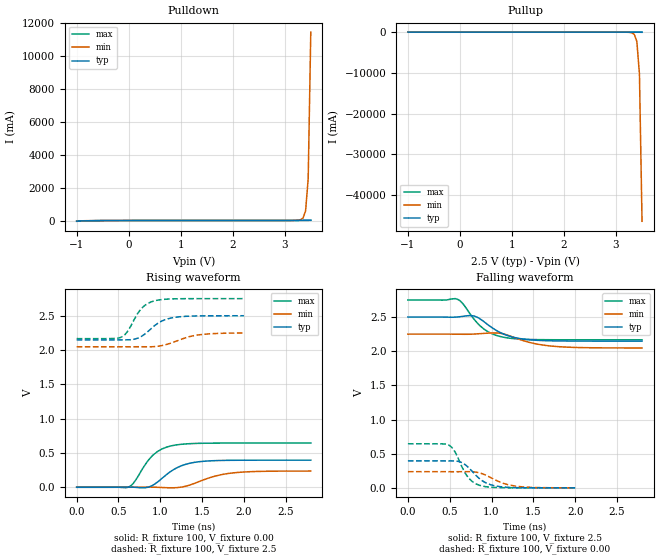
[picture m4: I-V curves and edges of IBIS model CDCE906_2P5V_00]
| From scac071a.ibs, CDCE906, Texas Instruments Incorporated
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|   Model   CDCE906_2P5V_00
[Model]   CDCE906_2P5V_00
Model_type   Output
Polarity   Non-Inverting
Vmeas  =   1.50V
Cref   =   3.00pF
Rref   =   100
Vref   =   0.00V
|Variable   typ   min   max
C_comp   1.472e-12   1.463e-12   1.490e-12
|Variable   typ   min   max
[Voltage range]   2.5   2.25   2.75
|Variable   typ   min   max
[Temperature range]  55   110   -15
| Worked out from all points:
|   slope of the pulldown table from 0 to 0.375 V, typ, clamps not added: 237 ohm
|   slope of the pullup table from 0 to 0.375 V, typ, clamps not added: 280 ohm
|   rising waveform, R_fixture 100, V_fixture 0.00: 20-80 % time 289ps typ, 368ps min, 242ps max; typ from 0 V to 0.395 V
|   falling waveform, R_fixture 100, V_fixture 2.5: 20-80 % time 309ps typ, 378ps min, 265ps max; typ from 2.5 V to 2.15 V
|   rising waveform, R_fixture 100, V_fixture 2.5: 20-80 % time 234ps typ, 304ps min, 184ps max; typ from 2.15 V to 2.5 V
|   falling waveform, R_fixture 100, V_fixture 0.00: 20-80 % time 216ps typ, 271ps min, 170ps max; typ from 0.395 V to 0 V
[Pulldown]
|Voltage   I(typ)   I(min)   I(max)
-1V       -35.71mA   -45.5mA    -45.21mA
-550mV    -3.792mA   -2.318mA   -6.183mA
3.15V     5.939mA    8.35mA     6.03mA
3.3V      9.436mA    45.5mA     7.442mA
3.35V     10.8mA     146.9mA    8.707mA
3.4V      12.31mA    585.3mA    10.16mA
3.45V     14.19mA    2.553A     11.78mA
3.5V      17.66mA    11.47A     13.54mA
[Pullup]
|Voltage   I(typ)   I(min)   I(max)
-1V       17.33mA    19.37mA    22.94mA
3.15V     -8.226mA   -15.73mA   -6.823mA
3.3V      -16.01mA   -135.6mA   -8.987mA
3.35V     -19.22mA   -527.9mA   -11.14mA
3.4V      -22.78mA   -2.287A    -13.98mA
3.45V     -27.22mA   -10.25A    -17.37mA
3.5V      -35.71mA   -46.44A    -21.23mA
[Ramp]
|Variable   typ   min   max
dV/dt_r  0.1198/2.217e-10   7.137e-02/3.024e-10   0.1977/1.698e-10
dV/dt_f  0.1063/2.346e-10   6.108e-02/3.162e-10   0.1762/1.879e-10
R_load  =  50
[Rising Waveform]
R_fixture   =   100
V_fixture   =   0.00
V_fixture_min   =   0.00
V_fixture_max   =   0.00
C_fixture   =   0.00
|Time   V(typ)   V(min)   V(max)
0s        0V         0V         0V
622.2ps   2.719mV    43.28uV    3.581mV
678.8ps   518.5uV    411.6uV    59.46mV
820.2ps   -6.651mV   2.31mV     330.3mV
905.1ps   25.58mV    1.538mV    459.4mV
1.018ns   127.5mV    -3.267mV   556.7mV
1.16ns    257.5mV    -7.72mV    610.2mV
1.414ns   363.9mV    59.48mV    638.4mV
1.838ns   392.7mV    204.7mV    644.1mV
2.8ns     394.9mV    236.3mV    644.6mV
[Falling Waveform]
R_fixture   =   100
V_fixture   =   2.5
V_fixture_min   =   2.25
V_fixture_max   =   2.75
C_fixture   =   0.00
|Time   V(typ)   V(min)   V(max)
0s        2.5V       2.25V      2.75V
593.9ps   2.501V     2.249V     2.76V
650.5ps   2.51V      2.248V     2.706V
791.9ps   2.515V     2.251V     2.466V
905.1ps   2.437V     2.261V     2.328V
1.018ns   2.334V     2.268V     2.249V
1.16ns    2.244V     2.248V     2.201V
1.358ns   2.182V     2.163V     2.177V
1.697ns   2.153V     2.078V     2.168V
2.8ns     2.148V     2.047V     2.167V
[Rising Waveform]
R_fixture   =   100
V_fixture   =   2.5
V_fixture_min   =   2.25
V_fixture_max   =   2.75
C_fixture   =   0.00
|Time   V(typ)   V(min)   V(max)
0s        2.147V     2.047V     2.166V
525.3ps   2.148V     2.047V     2.183V
606.1ps   2.149V     2.047V     2.266V
767.7ps   2.194V     2.048V     2.596V
848.5ps   2.266V     2.047V     2.677V
929.3ps   2.353V     2.05V      2.716V
1.051ns   2.439V     2.073V     2.739V
1.212ns   2.482V     2.139V     2.747V
1.495ns   2.498V     2.226V     2.749V
2ns       2.5V       2.249V     2.75V
[Falling Waveform]
R_fixture   =   100
V_fixture   =   0.00
V_fixture_min   =   0.00
V_fixture_max   =   0.00
C_fixture   =   0.00
|Time   V(typ)   V(min)   V(max)
0s        395.3mV    236.7mV    645.2mV
484.8ps   394.7mV    236.4mV    629.7mV
565.7ps   393.3mV    236.1mV    522.1mV
666.7ps   354.7mV    236.7mV    257.9mV
727.3ps   293.7mV    237mV      142mV
808.1ps   189.6mV    230.7mV    61.89mV
888.9ps   104.5mV    206.5mV    26.59mV
1.03ns    32.52mV    125.3mV    6.472mV
1.273ns   4.352mV    28.41mV    975.4uV
2ns       284.6uV    432.2uV    409.4uV
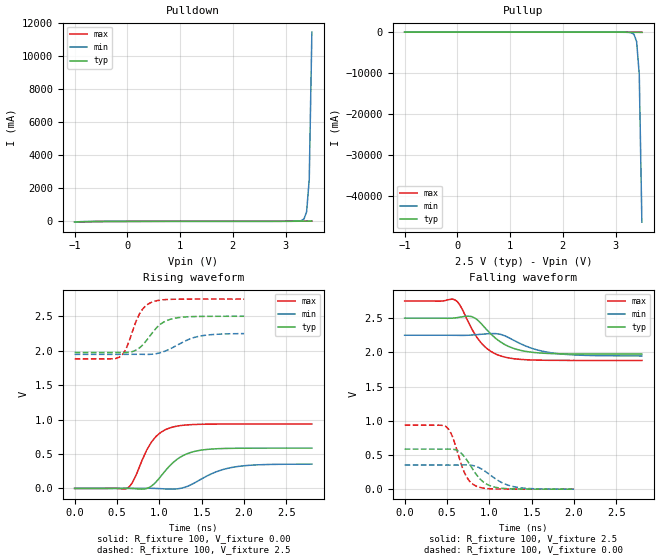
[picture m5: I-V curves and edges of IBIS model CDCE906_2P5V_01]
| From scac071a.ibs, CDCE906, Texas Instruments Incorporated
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|   Model   CDCE906_2P5V_01
[Model]   CDCE906_2P5V_01
Model_type   Output
Polarity   Non-Inverting
Vmeas  =   1.50V
Cref   =   3.00pF
Rref   =   100
Vref   =   0.00V
|Variable   typ   min   max
C_comp   1.485e-12   1.476e-12   1.505e-12
|Variable   typ   min   max
[Voltage range]   2.5   2.25   2.75
|Variable   typ   min   max
[Temperature range]  55   110   -15
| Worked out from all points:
|   slope of the pulldown table from 0 to 0.375 V, typ, clamps not added: 156 ohm
|   slope of the pullup table from 0 to 0.375 V, typ, clamps not added: 185 ohm
|   rising waveform, R_fixture 100, V_fixture 0.00: 20-80 % time 290ps typ, 374ps min, 234ps max; typ from 0 V to 0.585 V
|   falling waveform, R_fixture 100, V_fixture 2.5: 20-80 % time 318ps typ, 394ps min, 271ps max; typ from 2.5 V to 1.97 V
|   rising waveform, R_fixture 100, V_fixture 2.5: 20-80 % time 226ps typ, 308ps min, 171ps max; typ from 1.97 V to 2.5 V
|   falling waveform, R_fixture 100, V_fixture 0.00: 20-80 % time 209ps typ, 269ps min, 156ps max; typ from 0.586 V to 0 V
[Pulldown]
|Voltage   I(typ)   I(min)   I(max)
-1V       -37.87mA   -46.85mA   -48.45mA
-550mV    -5.193mA   -3.259mA   -8.289mA
3.15V     7.748mA    9.398mA    9.006mA
3.3V      11.25mA    46.55mA    10.43mA
3.35V     12.62mA    147.9mA    11.69mA
3.4V      14.13mA    586.4mA    13.15mA
3.45V     16.01mA    2.554A     14.77mA
3.5V      19.48mA    11.47A     16.53mA
[Pullup]
|Voltage   I(typ)   I(min)   I(max)
-1V       19.04mA    20.39mA    25.45mA
3.15V     -10.28mA   -16.96mA   -10.21mA
3.3V      -18.08mA   -136.8mA   -12.39mA
3.35V     -21.29mA   -529.1mA   -14.54mA
3.4V      -24.85mA   -2.288A    -17.38mA
3.45V     -29.29mA   -10.25A    -20.78mA
3.5V      -37.79mA   -46.45A    -24.64mA
[Ramp]
|Variable   typ   min   max
dV/dt_r  0.1790/2.263e-10   0.1068/3.154e-10   0.2941/1.671e-10
dV/dt_f  0.1592/2.461e-10   9.149e-02/3.314e-10   0.2635/1.908e-10
R_load  =  50
[Rising Waveform]
R_fixture   =   100
V_fixture   =   0.00
V_fixture_min   =   0.00
V_fixture_max   =   0.00
C_fixture   =   0.00
|Time   V(typ)   V(min)   V(max)
0s        0V         0V         0V
622.2ps   2.472mV    44.46uV    3.456mV
678.8ps   -238.3uV   415.1uV    78.94mV
905.1ps   32.72mV    1.273mV    671.1mV
1.018ns   177.2mV    -4.213mV   815.3mV
1.131ns   339.5mV    -10.08mV   882mV
1.301ns   489.7mV    17.28mV    919.5mV
1.527ns   561.3mV    157.8mV    932mV
1.952ns   583.4mV    322.4mV    934.9mV
2.8ns     585.1mV    352.4mV    935.3mV
[Falling Waveform]
R_fixture   =   100
V_fixture   =   2.5
V_fixture_min   =   2.25
V_fixture_max   =   2.75
C_fixture   =   0.00
|Time   V(typ)   V(min)   V(max)
0s        2.5V       2.25V      2.75V
593.9ps   2.503V     2.249V     2.765V
650.5ps   2.514V     2.248V     2.694V
791.9ps   2.523V     2.253V     2.344V
905.1ps   2.418V     2.264V     2.135V
1.018ns   2.267V     2.274V     2.013V
1.188ns   2.11V      2.239V     1.929V
1.471ns   2.006V     2.072V     1.89V
1.754ns   1.981V     1.989V     1.883V
2.8ns     1.974V     1.948V     1.882V
[Rising Waveform]
R_fixture   =   100
V_fixture   =   2.5
V_fixture_min   =   2.25
V_fixture_max   =   2.75
C_fixture   =   0.00
|Time   V(typ)   V(min)   V(max)
0s        1.974V     1.947V     1.881V
525.3ps   1.975V     1.947V     1.904V
606.1ps   1.975V     1.947V     2.025V
767.7ps   2.042V     1.947V     2.54V
848.5ps   2.149V     1.946V     2.661V
929.3ps   2.279V     1.951V     2.713V
1.051ns   2.415V     1.986V     2.74V
1.212ns   2.478V     2.081V     2.748V
1.495ns   2.498V     2.215V     2.749V
2ns       2.5V       2.248V     2.749V
[Falling Waveform]
R_fixture   =   100
V_fixture   =   0.00
V_fixture_min   =   0.00
V_fixture_max   =   0.00
C_fixture   =   0.00
|Time   V(typ)   V(min)   V(max)
0s        585.6mV    353mV      936.1mV
484.8ps   585.4mV    352.6mV    918.4mV
525.3ps   585.9mV    352.4mV    867.6mV
565.7ps   584.2mV    352.4mV    767.3mV
646.5ps   547.6mV    353.5mV    446.7mV
727.3ps   437.5mV    354.5mV    186.8mV
848.5ps   210.4mV    330.3mV    42.3mV
1.01ns    49.45mV    207.4mV    6.193mV
1.273ns   4.398mV    40.9mV     855.2uV
2ns       357.2uV    568.9uV    472.1uV
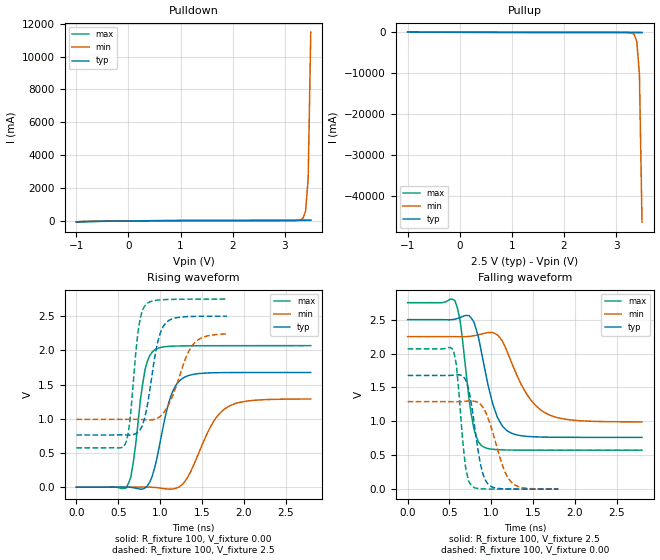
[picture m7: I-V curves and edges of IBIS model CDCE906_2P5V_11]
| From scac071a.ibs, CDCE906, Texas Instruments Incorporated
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|   Model   CDCE906_2P5V_11
[Model]   CDCE906_2P5V_11
Model_type   Output
Polarity   Non-Inverting
Vmeas  =   1.50V
Cref   =   3.00pF
Rref   =   100
Vref   =   0.00V
|Variable   typ   min   max
C_comp   1.514e-12   1.509e-12   1.522e-12
|Variable   typ   min   max
[Voltage range]   2.5   2.25   2.75
|Variable   typ   min   max
[Temperature range]  55   110   -15
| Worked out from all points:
|   slope of the pulldown table from 0 to 0.375 V, typ, clamps not added: 38 ohm
|   slope of the pullup table from 0 to 0.375 V, typ, clamps not added: 44.4 ohm
|   rising waveform, R_fixture 100, V_fixture 0.00: 20-80 % time 186ps typ, 303ps min, 126ps max; typ from 0 V to 1.68 V
|   falling waveform, R_fixture 100, V_fixture 2.5: 20-80 % time 197ps typ, 323ps min, 129ps max; typ from 2.5 V to 0.764 V
|   rising waveform, R_fixture 100, V_fixture 2.5: 20-80 % time 145ps typ, 228ps min, 99.9ps max; typ from 0.764 V to 2.5 V
|   falling waveform, R_fixture 100, V_fixture 0.00: 20-80 % time 127ps typ, 197ps min, 88.1ps max; typ from 1.68 V to 0 V
[Pulldown]
|Voltage   I(typ)   I(min)   I(max)
-1V       -56.52mA   -59.46mA   -75.1mA
650mV     15.46mA    9.848mA    23.99mA
3.15V     28.14mA    21.22mA    42.54mA
3.3V      31.71mA    58.42mA    44.05mA
3.35V     33.11mA    159.8mA    45.35mA
3.4V      34.64mA    598.2mA    46.84mA
3.45V     36.54mA    2.566A     48.49mA
3.5V      40.04mA    11.49A     50.28mA
[Pullup]
|Voltage   I(typ)   I(min)   I(max)
-1V       34.48mA    30.91mA    46.68mA
3.15V     -33.44mA   -30.81mA   -48.2mA
3.3V      -41.33mA   -150.7mA   -50.55mA
3.35V     -44.57mA   -543mA     -52.76mA
3.4V      -48.16mA   -2.302A    -55.66mA
3.45V     -52.63mA   -10.27A    -59.11mA
3.5V      -61.16mA   -46.46A    -63.02mA
[Ramp]
|Variable   typ   min   max
dV/dt_r  0.7049/2.021e-10   0.4775/3.268e-10   0.9568/1.378e-10
dV/dt_f  0.7013/2.211e-10   0.4227/3.076e-10   1.0143/1.483e-10
R_load  =  50
[Rising Waveform]
R_fixture   =   100
V_fixture   =   0.00
V_fixture_min   =   0.00
V_fixture_max   =   0.00
C_fixture   =   0.00
|Time   V(typ)   V(min)   V(max)
0s        0V         0V         0V
593.9ps   2.465mV    -55.52uV   -11.71mV
678.8ps   -6.747mV   516.4uV    356.7mV
820.2ps   -11.84mV   2.579mV    1.72V
933.3ps   276.2mV    -2.829mV   2.006V
1.103ns   1.235V     -27.79mV   2.058V
1.273ns   1.593V     49.06mV    2.065V
1.612ns   1.671V     904.9mV    2.067V
1.782ns   1.675V     1.153V     2.068V
2.8ns     1.677V     1.289V     2.068V
[Falling Waveform]
R_fixture   =   100
V_fixture   =   2.5
V_fixture_min   =   2.25
V_fixture_max   =   2.75
C_fixture   =   0.00
|Time   V(typ)   V(min)   V(max)
0s        2.5V       2.25V      2.75V
565.7ps   2.506V     2.249V     2.778V
622.2ps   2.528V     2.248V     2.52V
791.9ps   2.464V     2.262V     891.3mV
905.1ps   1.875V     2.294V     625.5mV
1.075ns   1.054V     2.273V     582mV
1.244ns   823.5mV    1.857V     577.4mV
1.471ns   775.2mV    1.316V     576mV
1.697ns   766.9mV    1.093V     575.8mV
2.8ns     764.3mV    992.8mV    575.5mV
[Rising Waveform]
R_fixture   =   100
V_fixture   =   2.5
V_fixture_min   =   2.25
V_fixture_max   =   2.75
C_fixture   =   0.00
|Time   V(typ)   V(min)   V(max)
0s        763.7mV    991.5mV    574.9mV
581.8ps   763.4mV    991.9mV    626.4mV
636.4ps   761.7mV    992.3mV    938.8mV
709.1ps   781.4mV    992.2mV    1.959V
745.5ps   812.5mV    991.3mV    2.345V
836.4ps   1.126V     983.9mV    2.676V
963.6ps   2.081V     1.006V     2.732V
1.073ns   2.405V     1.141V     2.742V
1.382ns   2.495V     2.066V     2.748V
1.8ns     2.499V     2.24V      2.749V
[Falling Waveform]
R_fixture   =   100
V_fixture   =   0.00
V_fixture_min   =   0.00
V_fixture_max   =   0.00
C_fixture   =   0.00
|Time   V(typ)   V(min)   V(max)
0s        1.677V     1.291V     2.069V
545.5ps   1.682V     1.29V      2.05V
581.8ps   1.686V     1.29V      1.838V
690.9ps   1.617V     1.296V     333.1mV
763.6ps   1.241V     1.301V     48.12mV
872.7ps   356mV      1.251V     5.914mV
963.6ps   71.01mV    1.037V     2.242mV
1.127ns   6.357mV    370.6mV    846.8uV
1.236ns   2.402mV    107.6mV    516.3uV
1.8ns     460.8uV    1.23mV     398.6uV
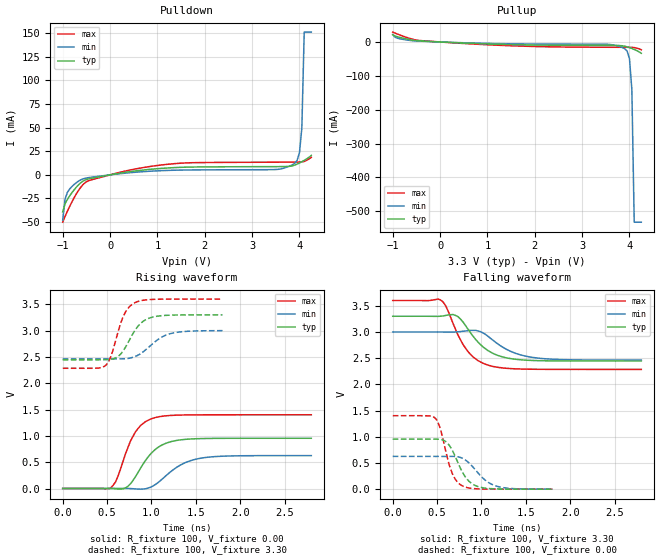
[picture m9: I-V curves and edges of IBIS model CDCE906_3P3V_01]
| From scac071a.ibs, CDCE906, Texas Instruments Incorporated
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|   Model   CDCE906_3P3V_01
[Model]   CDCE906_3P3V_01
Model_type   Output
Polarity   Non-Inverting
Vmeas  =   1.50V
Cref   =   3.00pF
Rref   =   100
Vref   =   0.00V
|Variable   typ   min   max
C_comp   1.468e-12   1.458e-12   1.487e-12
|Variable   typ   min   max
[Voltage range]   3.3   3.0   3.6
|Variable   typ   min   max
[Temperature range]  55   110   -15
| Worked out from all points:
|   slope of the pulldown table from 0 to 0.495 V, typ, clamps not added: 127 ohm
|   slope of the pullup table from 0 to 0.495 V, typ, clamps not added: 155 ohm
|   rising waveform, R_fixture 100, V_fixture 0.00: 20-80 % time 253ps typ, 311ps min, 208ps max; typ from 0 V to 0.955 V
|   falling waveform, R_fixture 100, V_fixture 3.30: 20-80 % time 284ps typ, 333ps min, 252ps max; typ from 3.3 V to 2.45 V
|   rising waveform, R_fixture 100, V_fixture 3.30: 20-80 % time 191ps typ, 249ps min, 152ps max; typ from 2.44 V to 3.3 V
|   falling waveform, R_fixture 100, V_fixture 0.00: 20-80 % time 174ps typ, 221ps min, 135ps max; typ from 0.955 V to 0.001 V
[Pulldown]
|Voltage   I(typ)   I(min)   I(max)
-1V       -39.23mA   -47.92mA   -50.09mA
-950mV    -30.59mA   -25.57mA   -43.96mA
-900mV    -25.89mA   -18.41mA   -38.39mA
-550mV    -6.01mA    -3.937mA   -9.244mA
250mV     2.142mA    1.44mA     3.203mA
1.2V      7.236mA    4.674mA    11.09mA
3.5V      8.728mA    5.687mA    13.41mA
3.9V      10.37mA    12.25mA    13.5mA
4V        12.61mA    23.52mA    13.6mA
4.05V     13.92mA    49.68mA    13.77mA
4.1V      15.33mA    151.1mA    14.17mA
4.25V     20.57mA    151.1mA    18.55mA
[Pullup]
|Voltage   I(typ)   I(min)   I(max)
-1V       21.2mA     21.69mA    29.14mA
-900mV    15.44mA    11.1mA     23.28mA
-500mV    3.869mA    2.904mA    5.378mA
200mV     -1.36mA    -1.01mA    -1.875mA
1.8V      -8.654mA   -5.89mA    -12.62mA
3.5V      -10.12mA   -6.708mA   -15.6mA
3.9V      -12.56mA   -19.84mA   -15.76mA
3.95V     -14.34mA   -26.91mA   -15.78mA
4V        -16.59mA   -49.45mA   -15.85mA
4.05V     -19.21mA   -139.7mA   -16.05mA
4.1V      -22.15mA   -532mA     -16.68mA
4.25V     -33.37mA   -532mA     -23.03mA
[Ramp]
|Variable   typ   min   max
dV/dt_r  0.2961/1.909e-10   0.1905/2.527e-10   0.4549/1.523e-10
dV/dt_f  0.2589/2.103e-10   0.1623/2.649e-10   0.3992/1.794e-10
R_load  =  50
[Rising Waveform]
R_fixture   =   100
V_fixture   =   0.00
V_fixture_min   =   0.00
V_fixture_max   =   0.00
C_fixture   =   0.00
|Time   V(typ)   V(min)   V(max)
0s        0V         0V         0V
537.4ps   2.14mV     316.2uV    4.606mV
593.9ps   -4.113mV   1.436mV    122.2mV
707.1ps   11.41mV    2.408mV    658.3mV
820.2ps   225.8mV    -7.482mV   1.078V
933.3ps   536.3mV    -5.156mV   1.271V
1.046ns   747.7mV    78.33mV    1.35V
1.329ns   924.7mV    449.4mV    1.396V
1.556ns   948.3mV    575.8mV    1.4V
2.8ns     954.6mV    625mV      1.401V
[Falling Waveform]
R_fixture   =   100
V_fixture   =   3.30
V_fixture_min   =   3.00
V_fixture_max   =   3.60
C_fixture   =   0.00
|Time   V(typ)   V(min)   V(max)
0s        3.3V       3V         3.6V
537.4ps   3.301V     3V         3.613V
593.9ps   3.314V     2.999V     3.507V
707.1ps   3.316V     3V         3.053V
848.5ps   3.052V     3.025V     2.623V
989.9ps   2.757V     3.005V     2.427V
1.075ns   2.643V     2.915V     2.366V
1.301ns   2.5V       2.652V     2.304V
1.556ns   2.458V     2.52V      2.289V
2.8ns     2.446V     2.463V     2.286V
[Rising Waveform]
R_fixture   =   100
V_fixture   =   3.30
V_fixture_min   =   3.00
V_fixture_max   =   3.60
C_fixture   =   0.00
|Time   V(typ)   V(min)   V(max)
0s        2.445V     2.463V     2.284V
400ps     2.445V     2.462V     2.288V
490.9ps   2.447V     2.463V     2.35V
545.5ps   2.454V     2.463V     2.525V
690.9ps   2.64V      2.464V     3.299V
745.5ps   2.802V     2.474V     3.444V
818.2ps   3.015V     2.51V      3.535V
963.6ps   3.229V     2.677V     3.588V
1.2ns     3.293V     2.936V     3.598V
1.8ns     3.299V     2.999V     3.599V
[Falling Waveform]
R_fixture   =   100
V_fixture   =   0.00
V_fixture_min   =   0.00
V_fixture_max   =   0.00
C_fixture   =   0.00
|Time   V(typ)   V(min)   V(max)
0s        955.4mV    625.5mV    1.402V
472.7ps   954.7mV    625.3mV    1.364V
527.3ps   952.1mV    624.9mV    1.198V
600ps     905.5mV    625.2mV    704.2mV
672.7ps   737mV      626mV      292.7mV
727.3ps   534mV      619.9mV    139.8mV
800ps     280.4mV    576.9mV    51.09mV
927.3ps   71.73mV    377.4mV    9.513mV
1.145ns   7.037mV    71.61mV    1.331mV
1.8ns     532.3uV    703.5uV    683.8uV
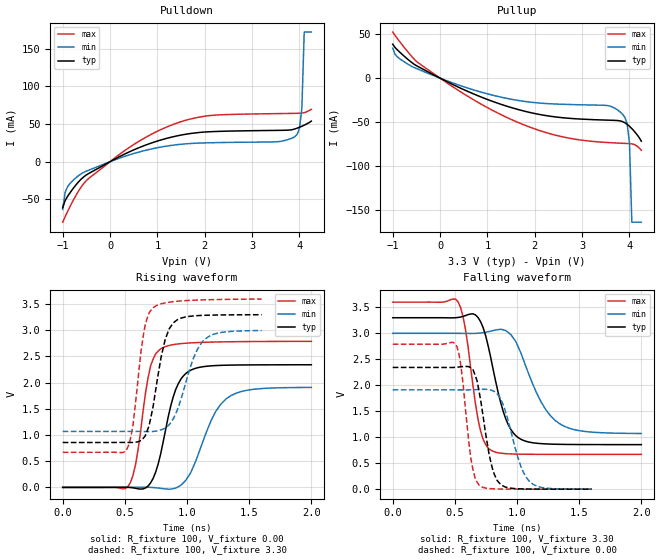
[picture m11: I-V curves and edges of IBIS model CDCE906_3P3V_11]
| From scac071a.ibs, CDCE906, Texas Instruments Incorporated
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|   Model   CDCE906_3P3V_11
[Model]   CDCE906_3P3V_11
Model_type   Output
Polarity   Non-Inverting
Vmeas  =   1.50V
Cref   =   3.00pF
Rref   =   100
Vref   =   0.00V
|Variable   typ   min   max
C_comp   1.481e-12   1.475e-12   1.487e-12
|Variable   typ   min   max
[Voltage range]   3.3   3.0   3.6
|Variable   typ   min   max
[Temperature range]  55   110   -15
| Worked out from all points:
|   slope of the pulldown table from 0 to 0.495 V, typ, clamps not added: 31.9 ohm
|   slope of the pullup table from 0 to 0.495 V, typ, clamps not added: 38.1 ohm
|   rising waveform, R_fixture 100, V_fixture 0.00: 20-80 % time 140ps typ, 205ps min, 104ps max; typ from 0 V to 2.34 V
|   falling waveform, R_fixture 100, V_fixture 3.30: 20-80 % time 149ps typ, 223ps min, 105ps max; typ from 3.3 V to 0.858 V
|   rising waveform, R_fixture 100, V_fixture 3.30: 20-80 % time 113ps typ, 161ps min, 88.2ps max; typ from 0.857 V to 3.3 V
|   falling waveform, R_fixture 100, V_fixture 0.00: 20-80 % time 99.5ps typ, 138ps min, 75.6ps max; typ from 2.34 V to 0.001 V
[Pulldown]
|Voltage   I(typ)   I(min)   I(max)
-1V       -61.1mA    -63.35mA   -80.35mA
-950mV    -51.82mA   -41.05mA   -73.18mA
-900mV    -46.35mA   -33.49mA   -66.53mA
-600mV    -22.55mA   -15.78mA   -32.66mA
250mV     8.326mA    5.81mA     12.04mA
1.05V     28.36mA    19.12mA    41.92mA
2.05V     39.57mA    25.04mA    60.82mA
3.9V      43.41mA    33.12mA    64.17mA
4V        45.71mA    44.43mA    64.35mA
4.05V     47.05mA    70.61mA    64.56mA
4.1V      48.5mA     172.1mA    64.99mA
4.25V     53.85mA    172.1mA    69.5mA
[Pullup]
|Voltage   I(typ)   I(min)   I(max)
-1V       38.78mA    34.22mA    52.61mA
-900mV    32.2mA     24.2mA     45.13mA
-500mV    14.32mA    11.08mA    19.2mA
1.25V     -29.18mA   -21.21mA   -40.64mA
2.5V      -44.66mA   -29.65mA   -65.9mA
3.5V      -47.86mA   -31.11mA   -73.33mA
3.75V     -48.38mA   -36.4mA    -74.08mA
3.9V      -50.78mA   -44.48mA   -74.45mA
3.95V     -52.62mA   -51.58mA   -74.57mA
4V        -54.91mA   -74.15mA   -74.72mA
4.05V     -57.59mA   -164.4mA   -75.02mA
4.25V     -71.92mA   -164.4mA   -82.32mA
[Ramp]
|Variable   typ   min   max
dV/dt_r  1.0380/1.636e-10   0.7767/2.243e-10   1.3273/1.069e-10
dV/dt_f  1.0670/1.793e-10   0.7320/2.384e-10   1.4149/1.130e-10
R_load  =  50
[Rising Waveform]
R_fixture   =   100
V_fixture   =   0.00
V_fixture_min   =   0.00
V_fixture_max   =   0.00
C_fixture   =   0.00
|Time   V(typ)   V(min)   V(max)
0s        0V         0V         0V
525.3ps   1.355mV    300.4uV    18.36mV
585.9ps   -17.03mV   1.506mV    431.2mV
707.1ps   85.8mV     155.1uV    2.32V
787.9ps   636.1mV    -17.85mV   2.645V
888.9ps   1.726V     -25.04mV   2.725V
1.01ns    2.21V      207.5mV    2.756V
1.192ns   2.32V      1.267V     2.774V
1.313ns   2.332V     1.686V     2.779V
2ns       2.341V     1.908V     2.788V
[Falling Waveform]
R_fixture   =   100
V_fixture   =   3.30
V_fixture_min   =   3.00
V_fixture_max   =   3.60
C_fixture   =   0.00
|Time   V(typ)   V(min)   V(max)
0s        3.299V     2.999V     3.599V
525.3ps   3.304V     2.999V     3.606V
585.9ps   3.34V      2.997V     3.067V
686.9ps   3.303V     3.002V     1.336V
787.9ps   2.542V     3.041V     754.5mV
909.1ps   1.356V     3.053V     683.3mV
1.03ns    961.7mV    2.626V     673.8mV
1.192ns   877.1mV    1.688V     670.9mV
1.333ns   863.7mV    1.276V     670mV
2ns       857.7mV    1.071V     670.1mV
[Rising Waveform]
R_fixture   =   100
V_fixture   =   3.30
V_fixture_min   =   3.00
V_fixture_max   =   3.60
C_fixture   =   0.00
|Time   V(typ)   V(min)   V(max)
0s        856.9mV    1.068V     669.3mV
517.2ps   857.9mV    1.068V     734.5mV
565.7ps   858.2mV    1.069V     1.196V
662.6ps   978.5mV    1.066V     3.091V
727.3ps   1.545V     1.068V     3.43V
824.2ps   2.821V     1.133V     3.523V
888.9ps   3.138V     1.307V     3.546V
1.051ns   3.273V     2.457V     3.573V
1.131ns   3.284V     2.797V     3.58V
1.6ns     3.296V     2.995V     3.595V
[Falling Waveform]
R_fixture   =   100
V_fixture   =   0.00
V_fixture_min   =   0.00
V_fixture_max   =   0.00
C_fixture   =   0.00
|Time   V(typ)   V(min)   V(max)
0s        2.343V     1.912V     2.79V
501ps     2.344V     1.911V     2.802V
549.5ps   2.356V     1.911V     2.355V
630.3ps   2.33V      1.911V     571.8mV
694.9ps   1.88V      1.919V     77.4mV
791.9ps   497.9mV    1.906V     9.479mV
872.7ps   82.47mV    1.716V     3.012mV
1.018ns   7.309mV    526.6mV    866.6uV
1.099ns   3.03mV     153.2mV    745.3uV
1.6ns     531.7uV    1.23mV     498.9uV
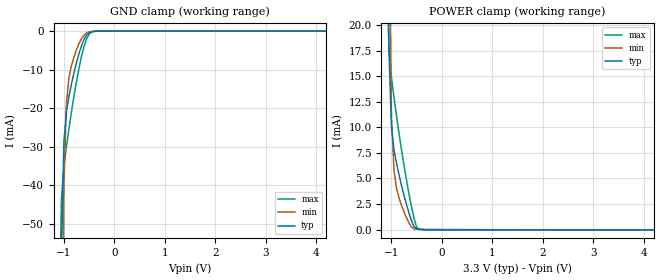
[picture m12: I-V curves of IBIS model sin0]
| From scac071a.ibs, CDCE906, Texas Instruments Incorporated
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|   Model   sin0
[Model]   sin0
Model_type   Input
Polarity   Non-Inverting
Vinl   =   1.08V
Vinh   =   2.10V
|Variable   typ   min   max
C_comp   7.047e-13   7.029e-13   7.141e-13
|Variable   typ   min   max
[Voltage range]   3.3   3.0   3.6
|Variable   typ   min   max
[Temperature range]  55   110   -15
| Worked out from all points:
|   GND clamp passes 1 mA (typ) near -0.55 V on its own axis
|   POWER clamp passes 1 mA (typ) near -0.61 V on its own axis
| Note: The Input-Buffer model contains a Pull-Up resistor of
|   170 kOhm(typ) 250 kOhm(min) and 130 kOhm(max).
[GND_clamp]
|Volts   typ   min   max
-1.2V     -6.266A    -10.23A    -3.28A
-1.1V     -212.2mA   -514.8mA   -81.06mA
-1.05V    -58.07mA   -127.1mA   -43.68mA
-1V       -28.78mA   -39.72mA   -35.25mA
-950mV    -20.95mA   -18.56mA   -30.04mA
-900mV    -16.92mA   -12.08mA   -25.37mA
-800mV    -10.8mA    -6.711mA   -16.85mA
-700mV    -5.781mA   -3.233mA   -9.56mA
-550mV    -1.04mA    -481.1uA   -2.014mA
-450mV    -153.1uA   -83.08uA   -255.8uA
-350mV    -35.16uA   -25.35uA   -41.82uA
4.2V      0A         0A         0A
[POWER_clamp]
|Volts   typ   min   max
-1.2V     1.548A     2.521A     817mA
-1.1V     56.09mA    128.7mA    27.64mA
-1.05V    17.73mA    32.97mA    17.7mA
-1V       10.14mA    11.27mA    14.92mA
-950mV    7.841mA    5.863mA    12.96mA
-900mV    6.496mA    4.078mA    11.16mA
-750mV    3.336mA    1.739mA    6.26mA
-600mV    867.1uA    241.5uA    2.201mA
-550mV    286.9uA    82.97uA    1.092mA
-500mV    80.62uA    44.26uA    239.5uA
-400mV    16.97uA    9.525uA    27.27uA
4.2V      -23.26uA   -16.87uA   -29.41uA
